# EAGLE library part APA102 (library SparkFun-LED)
APA102 Addressable RGB LED Used in manufacturing of various products at SparkFun Packages: 5050 2020 SparkFun Products: SparkFun Lumenati Boards

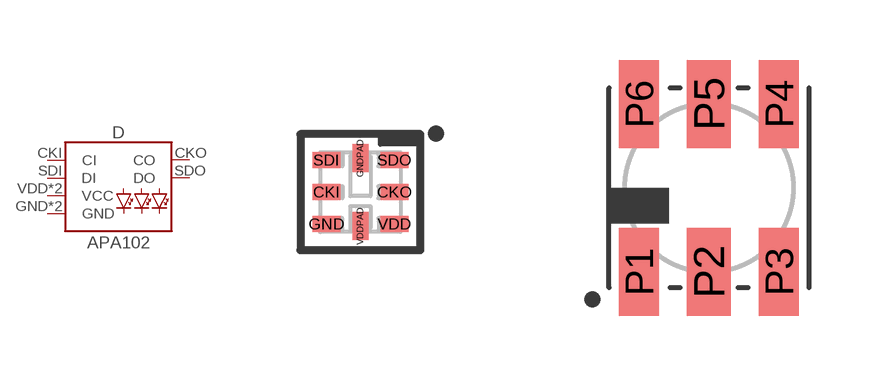
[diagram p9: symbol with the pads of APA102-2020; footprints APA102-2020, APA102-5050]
Designator prefix D

## APA1022020 (PROD_ID: DIO-13883)  [APA102-2020]
CKI  CI
CKO  CO
GND  GND
GNDPAD  GND
SDI  DI
SDO  DO
VDD  VCC
VDDPAD  VCC

## APA1025050 (PROD_ID: DIO-13739)  [APA102-5050]
P1  DI
P2  CI
P3  GND
P4  VCC
P5  CO
P6  DO

## APA1022020-TEST (PROD_ID: DIO-13883)  [APA102-2020-TEST]
Pads as for APA102-2020

## Footprint APA102-2020 (pad centres in mm)
APA102-2020 Specifications: Pin count: 8 Size: 2.0 x 2.0 mm Datasheet referenced for footprint: APA102-2020
smd 0.7 x 0.4: CKI -0.85,0; CKO 0.85,0; GND -0.85,-0.8; SDI -0.85,0.8; SDO 0.85,0.8; VDD 0.85,-0.8
smd 0.4 x 0.7: GNDPAD 0,0.85; VDDPAD 0,-0.85

## Footprint APA102-5050 (pad centres in mm)
APA102C Specifications: Pin count: 6 Size: 5.0 x 5.0 mm Datasheet referenced for footprint: APA102C
smd 1 x 2.2: P1 -1.75,-2.1; P3 1.75,-2.1; P4 1.75,2.1; P6 -1.75,2.1
smd 1.1 x 2.2: P2 0,-2.1; P5 0,2.1

## Footprint APA102-2020-TEST (pad centres in mm)
smd 0.5 x 0.3: CKI 0.7,0; CKO -0.7,0; GND 0.7,0.8; SDI 0.7,-0.8; SDO -0.7,-0.8; VDD -0.7,0.8
smd 0.3 x 0.5: GNDPAD 0,-0.7; VDDPAD 0,0.7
